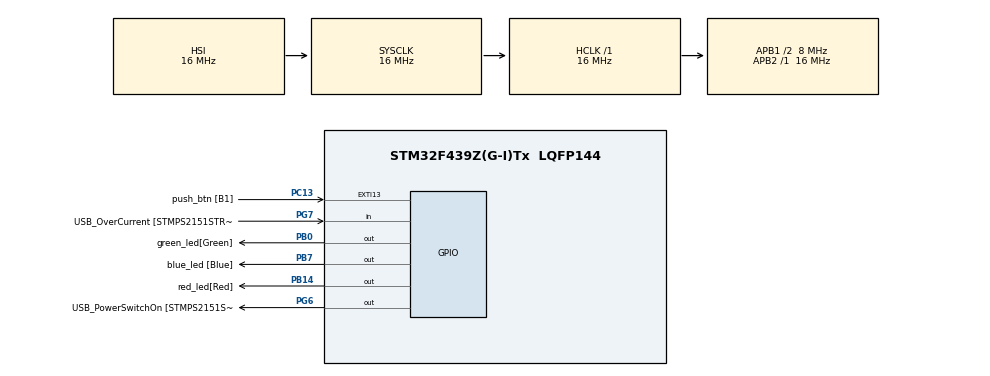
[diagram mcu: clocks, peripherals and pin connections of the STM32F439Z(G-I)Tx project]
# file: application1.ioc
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Mcu.Family=STM32F4
Mcu.Name=STM32F439Z(G-I)Tx
Mcu.Package=LQFP144
NVIC.PriorityGroup=NVIC_PRIORITYGROUP_4
PA1.GPIO_Label=RMII_REF_CLK [LAN8742A-CZ-TR_REFCLK0]
PA1.Signal=ETH_REF_CLK
PA10.GPIO_Label=USB_ID
PA10.Signal=USB_OTG_FS_ID
PA11.GPIO_Label=USB_DM
PA11.Signal=USB_OTG_FS_DM
PA12.GPIO_Label=USB_DP
PA12.Signal=USB_OTG_FS_DP
PA13.GPIO_Label=TMS
PA13.Signal=SYS_JTMS-SWDIO
PA14.GPIO_Label=TCK
PA14.Signal=SYS_JTCK-SWCLK
PA2.GPIO_Label=RMII_MDIO [LAN8742A-CZ-TR_MDIO]
PA2.Signal=ETH_MDIO
PA7.GPIO_Label=RMII_CRS_DV [LAN8742A-CZ-TR_CRS_DV]
PA7.Signal=ETH_CRS_DV
PA8.GPIO_Label=USB_SOF [TP1]
PA8.Signal=USB_OTG_FS_SOF
PA9.GPIO_Label=USB_VBUS
PA9.Signal=USB_OTG_FS_VBUS
PB0.GPIO_Label=green_led[Green]
PB0.Signal=GPIO_Output
PB13.GPIO_Label=RMII_TXD1 [LAN8742A-CZ-TR_TXD1]
PB13.Signal=ETH_TXD1
PB14.GPIO_Label=red_led[Red]
PB14.Signal=GPIO_Output
PB7.GPIO_Label=blue_led [Blue]
PB7.Signal=GPIO_Output
PC1.GPIO_Label=RMII_MDC [LAN8742A-CZ-TR_MDC]
PC1.Signal=ETH_MDC
PC13.GPIO_Label=push_btn [B1]
PC13.Signal=GPXTI13
PC14/OSC32_IN.Signal=RCC_OSC32_IN
PC15/OSC32_OUT.Signal=RCC_OSC32_OUT
PC4.GPIO_Label=RMII_RXD0 [LAN8742A-CZ-TR_RXD0]
PC4.Signal=ETH_RXD0
PC5.GPIO_Label=RMII_RXD1 [LAN8742A-CZ-TR_RXD1]
PC5.Signal=ETH_RXD1
PD8.GPIO_Label=STLK_RX [STM32F103CBT6_PA3]
PD8.Signal=USART3_TX
PD9.GPIO_Label=STLK_TX [STM32F103CBT6_PA2]
PD9.Signal=USART3_RX
PG11.GPIO_Label=RMII_TX_EN [LAN8742A-CZ-TR_TXEN]
PG11.Signal=ETH_TX_EN
PG13.GPIO_Label=RMII_TXD0 [LAN8742A-CZ-TR_TXD0]
PG13.Signal=ETH_TXD0
PG6.GPIO_Label=USB_PowerSwitchOn [STMPS2151STR_EN]
PG6.Signal=GPIO_Output
PG7.GPIO_Label=USB_OverCurrent [STMPS2151STR_FAULT]
PG7.Signal=GPIO_Input
PH0/OSC_IN.GPIO_Label=MCO [STM32F103CBT6_PA8]
PH0/OSC_IN.Signal=RCC_OSC_IN
PH1/OSC_OUT.Signal=RCC_OSC_OUT
ProjectManager.HeapSize=0x200
ProjectManager.StackSize=0x400
ProjectManager.TargetToolchain=STM32CubeIDE
RCC.48MHZClocksFreq_Value=48000000
RCC.AHBFreq_Value=16000000
RCC.APB1CLKDivider=RCC_HCLK_DIV2
RCC.APB1Freq_Value=8000000
RCC.APB1TimFreq_Value=16000000
RCC.APB2Freq_Value=16000000
RCC.APB2TimFreq_Value=16000000
RCC.CortexFreq_Value=16000000
RCC.HCLKFreq_Value=16000000
RCC.HSE_VALUE=8000000
RCC.HSI_VALUE=16000000
RCC.LSE_VALUE=32768
RCC.PLLMUL=RCC_PLL_MUL9
RCC.PRESCALERUSB=RCC_USBCLKSOURCE_PLL_DIV1_5
RCC.SYSCLKFreq_VALUE=16000000
RCC.SYSCLKSourceVirtual=RCC_SYSCLKSOURCE_PLLCLK
RCC.USBFreq_Value=48000000
RCC.VCOOutputFreq_Value=192000000
board=NUCLEO-F439ZI

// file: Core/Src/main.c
/* USER CODE BEGIN Header */
/**
  ******************************************************************************
  * @file           : main.c
  * @brief          : Main program body
  ******************************************************************************
  * @attention
  *
  * Copyright (c) 2022 STMicroelectronics.
  * All rights reserved.
  *
  * This software is licensed under terms that can be found in the LICENSE file
  * in the root directory of this software component.
  * If no LICENSE file comes with this software, it is provided AS-IS.
  *
  ******************************************************************************
  */
/* USER CODE END Header */
#include "main.h"
#include "bootloader.h"

void SystemClock_Config(void);
static void MX_GPIO_Init(void);

int main(void)
{
  /* USER CODE BEGIN 1 */
	__enable_irq();
  /* USER CODE END 1 */

  /* MCU Configuration--------------------------------------------------------*/

  /* Reset of all peripherals, Initializes the Flash interface and the Systick. */
  HAL_Init();

  /* Configure the system clock */
  SystemClock_Config();

  /* Initialize all configured peripherals */
  MX_GPIO_Init();

  /* Infinite loop */
  while (1)
  {
	  HAL_GPIO_TogglePin(red_led_GPIO_Port, red_led_Pin);
	  HAL_Delay(1000);

	  //bootloader_switch_to_inactive_bank();
	  //bootloader_reboot();

  }
}

void SystemClock_Config(void)
{
  RCC_OscInitTypeDef RCC_OscInitStruct = {0};
  RCC_ClkInitTypeDef RCC_ClkInitStruct = {0};

  /** Configure the main internal regulator output voltage
  */
  __HAL_RCC_PWR_CLK_ENABLE();
  __HAL_PWR_VOLTAGESCALING_CONFIG(PWR_REGULATOR_VOLTAGE_SCALE3);

  /** Initializes the RCC Oscillators according to the specified parameters
  * in the RCC_OscInitTypeDef structure.
  */
  RCC_OscInitStruct.OscillatorType = RCC_OSCILLATORTYPE_HSI;
  RCC_OscInitStruct.HSIState = RCC_HSI_ON;
  RCC_OscInitStruct.HSICalibrationValue = RCC_HSICALIBRATION_DEFAULT;
  RCC_OscInitStruct.PLL.PLLState = RCC_PLL_NONE;
  if (HAL_RCC_OscConfig(&RCC_OscInitStruct) != HAL_OK)
  {
    Error_Handler();
  }

  /** Initializes the CPU, AHB and APB buses clocks
  */
  RCC_ClkInitStruct.ClockType = RCC_CLOCKTYPE_HCLK|RCC_CLOCKTYPE_SYSCLK
                              |RCC_CLOCKTYPE_PCLK1|RCC_CLOCKTYPE_PCLK2;
  RCC_ClkInitStruct.SYSCLKSource = RCC_SYSCLKSOURCE_HSI;
  RCC_ClkInitStruct.AHBCLKDivider = RCC_SYSCLK_DIV1;
  RCC_ClkInitStruct.APB1CLKDivider = RCC_HCLK_DIV2;
  RCC_ClkInitStruct.APB2CLKDivider = RCC_HCLK_DIV1;

  if (HAL_RCC_ClockConfig(&RCC_ClkInitStruct, FLASH_LATENCY_0) != HAL_OK)
  {
    Error_Handler();
  }
}

static void MX_GPIO_Init(void)
{
  GPIO_InitTypeDef GPIO_InitStruct = {0};

  /* GPIO Ports Clock Enable */
  __HAL_RCC_GPIOE_CLK_ENABLE();
  __HAL_RCC_GPIOC_CLK_ENABLE();
  __HAL_RCC_GPIOF_CLK_ENABLE();
  __HAL_RCC_GPIOH_CLK_ENABLE();
  __HAL_RCC_GPIOB_CLK_ENABLE();
  __HAL_RCC_GPIOD_CLK_ENABLE();
  __HAL_RCC_GPIOA_CLK_ENABLE();

  /*Configure GPIO pin Output Level */
  HAL_GPIO_WritePin(GPIOE, GPIO_PIN_3, GPIO_PIN_RESET);

  /*Configure GPIO pin Output Level */
  HAL_GPIO_WritePin(GPIOF, GPIO_PIN_7|GPIO_PIN_8|GPIO_PIN_9, GPIO_PIN_RESET);

  /*Configure GPIO pin Output Level */
  HAL_GPIO_WritePin(GPIOB, green_led_Pin|red_led_Pin|blue_led_Pin, GPIO_PIN_RESET);

  /*Configure GPIO pins : PE2 PE4 PE5 PE6 */
  GPIO_InitStruct.Pin = GPIO_PIN_2|GPIO_PIN_4|GPIO_PIN_5|GPIO_PIN_6;
  GPIO_InitStruct.Mode = GPIO_MODE_INPUT;
  GPIO_InitStruct.Pull = GPIO_PULLDOWN;
  HAL_GPIO_Init(GPIOE, &GPIO_InitStruct);

  /*Configure GPIO pin : PE3 */
  GPIO_InitStruct.Pin = GPIO_PIN_3;
  GPIO_InitStruct.Mode = GPIO_MODE_OUTPUT_PP;
  GPIO_InitStruct.Pull = GPIO_NOPULL;
  GPIO_InitStruct.Speed = GPIO_SPEED_FREQ_LOW;
  HAL_GPIO_Init(GPIOE, &GPIO_InitStruct);

  /*Configure GPIO pin : push_btn_Pin */
  GPIO_InitStruct.Pin = push_btn_Pin;
  GPIO_InitStruct.Mode = GPIO_MODE_IT_RISING;
  GPIO_InitStruct.Pull = GPIO_PULLUP;
  HAL_GPIO_Init(push_btn_GPIO_Port, &GPIO_InitStruct);

  /*Configure GPIO pins : PF7 PF8 PF9 */
  GPIO_InitStruct.Pin = GPIO_PIN_7|GPIO_PIN_8|GPIO_PIN_9;
  GPIO_InitStruct.Mode = GPIO_MODE_OUTPUT_PP;
  GPIO_InitStruct.Pull = GPIO_NOPULL;
  GPIO_InitStruct.Speed = GPIO_SPEED_FREQ_LOW;
  HAL_GPIO_Init(GPIOF, &GPIO_InitStruct);

  /*Configure GPIO pins : green_led_Pin red_led_Pin blue_led_Pin */
  GPIO_InitStruct.Pin = green_led_Pin|red_led_Pin|blue_led_Pin;
  GPIO_InitStruct.Mode = GPIO_MODE_OUTPUT_PP;
  GPIO_InitStruct.Pull = GPIO_NOPULL;
  GPIO_InitStruct.Speed = GPIO_SPEED_FREQ_LOW;
  HAL_GPIO_Init(GPIOB, &GPIO_InitStruct);

  /*Configure GPIO pin : RMII_TXD1_Pin */
  GPIO_InitStruct.Pin = RMII_TXD1_Pin;
  GPIO_InitStruct.Mode = GPIO_MODE_AF_PP;
  GPIO_InitStruct.Pull = GPIO_NOPULL;
  GPIO_InitStruct.Speed = GPIO_SPEED_FREQ_VERY_HIGH;
  GPIO_InitStruct.Alternate = GPIO_AF11_ETH;
  HAL_GPIO_Init(RMII_TXD1_GPIO_Port, &GPIO_InitStruct);

  /*Configure GPIO pins : STLK_RX_Pin STLK_TX_Pin */
  GPIO_InitStruct.Pin = STLK_RX_Pin|STLK_TX_Pin;
  GPIO_InitStruct.Mode = GPIO_MODE_AF_PP;
  GPIO_InitStruct.Pull = GPIO_NOPULL;
  GPIO_InitStruct.Speed = GPIO_SPEED_FREQ_VERY_HIGH;
  GPIO_InitStruct.Alternate = GPIO_AF7_USART3;
  HAL_GPIO_Init(GPIOD, &GPIO_InitStruct);

}

void Error_Handler(void)
{
  __disable_irq();
  while (1)
  {
  }
}
